###############################################################
#  Generated by:      Cadence Innovus 20.13-s083_1
#  OS:                Linux x86_64(Host ID rice-503-20-north)
#  Generated on:      Thu May  5 21:50:22 2022
#  Design:            ringosc
#  Command:           write_lef_abstract -5.8 -extractBlockObs /home/users/xingyuni/ee372/aloe-sky130/aloe/layout/output/lef/ro_top2_0.lef
###############################################################

VERSION 5.8 ;

BUSBITCHARS "[]" ;
DIVIDERCHAR "/" ;

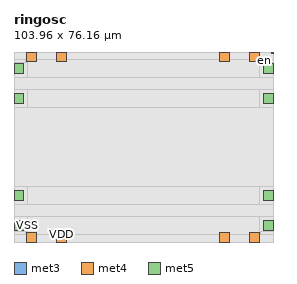
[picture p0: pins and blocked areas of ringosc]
MACRO ringosc
  CLASS BLOCK ;
  SIZE 103.960000 BY 76.160000 ;
  FOREIGN ringosc 0.000000 0.000000 ;
  ORIGIN 0 0 ;
  SYMMETRY X Y R90 ;
  PIN en
    DIRECTION INPUT ;
    USE SIGNAL ;
    PORT
      LAYER met3 ;
        RECT 103.160000 75.550000 103.960000 75.850000 ;
    END
  END en
  PIN clk
    DIRECTION INPUT ;
    USE SIGNAL ;
  END clk
  PIN VSS
    DIRECTION INOUT ;
    USE GROUND ;
    PORT
      LAYER met4 ;
        RECT 4.980000 0.000000 8.980000 4.000000 ;
    END
    PORT
      LAYER met4 ;
        RECT 4.980000 72.160000 8.980000 76.160000 ;
    END
    PORT
      LAYER met4 ;
        RECT 94.550000 0.000000 98.550000 4.000000 ;
    END
    PORT
      LAYER met4 ;
        RECT 94.550000 72.160000 98.550000 76.160000 ;
    END
    PORT
      LAYER met5 ;
        RECT 0.000000 4.560000 4.000000 8.560000 ;
    END
    PORT
      LAYER met5 ;
        RECT 99.960000 4.560000 103.960000 8.560000 ;
    END
    PORT
      LAYER met5 ;
        RECT 0.000000 67.360000 4.000000 71.360000 ;
    END
    PORT
      LAYER met5 ;
        RECT 99.960000 67.360000 103.960000 71.360000 ;
    END
  END VSS
  PIN VDD
    DIRECTION INOUT ;
    USE POWER ;
    PORT
      LAYER met4 ;
        RECT 16.980000 0.000000 20.980000 4.000000 ;
    END
    PORT
      LAYER met4 ;
        RECT 16.980000 72.160000 20.980000 76.160000 ;
    END
    PORT
      LAYER met4 ;
        RECT 82.550000 0.000000 86.550000 4.000000 ;
    END
    PORT
      LAYER met4 ;
        RECT 82.550000 72.160000 86.550000 76.160000 ;
    END
    PORT
      LAYER met5 ;
        RECT 0.000000 16.560000 4.000000 20.560000 ;
    END
    PORT
      LAYER met5 ;
        RECT 99.960000 16.560000 103.960000 20.560000 ;
    END
    PORT
      LAYER met5 ;
        RECT 0.000000 55.360000 4.000000 59.360000 ;
    END
    PORT
      LAYER met5 ;
        RECT 99.960000 55.360000 103.960000 59.360000 ;
    END
  END VDD
  OBS
    LAYER li1 ;
      RECT 0.000000 0.000000 103.960000 76.160000 ;
    LAYER met1 ;
      RECT 0.000000 0.000000 103.960000 76.160000 ;
    LAYER met2 ;
      RECT 0.000000 0.000000 103.960000 76.160000 ;
    LAYER met3 ;
      RECT 0.000000 75.150000 102.760000 76.160000 ;
      RECT 0.000000 0.000000 103.960000 75.150000 ;
    LAYER met4 ;
      RECT 98.950000 71.760000 103.960000 76.160000 ;
      RECT 86.950000 71.760000 94.150000 76.160000 ;
      RECT 21.380000 71.760000 82.150000 76.160000 ;
      RECT 9.380000 71.760000 16.580000 76.160000 ;
      RECT 0.000000 71.760000 4.580000 76.160000 ;
      RECT 0.000000 4.400000 103.960000 71.760000 ;
      RECT 98.950000 0.000000 103.960000 4.400000 ;
      RECT 86.950000 0.000000 94.150000 4.400000 ;
      RECT 21.380000 0.000000 82.150000 4.400000 ;
      RECT 9.380000 0.000000 16.580000 4.400000 ;
      RECT 0.000000 0.000000 4.580000 4.400000 ;
    LAYER met5 ;
      RECT 0.000000 72.960000 103.960000 76.160000 ;
      RECT 5.600000 65.760000 98.360000 72.960000 ;
      RECT 0.000000 60.960000 103.960000 65.760000 ;
      RECT 5.600000 53.760000 98.360000 60.960000 ;
      RECT 0.000000 22.160000 103.960000 53.760000 ;
      RECT 5.600000 14.960000 98.360000 22.160000 ;
      RECT 0.000000 10.160000 103.960000 14.960000 ;
      RECT 5.600000 2.960000 98.360000 10.160000 ;
      RECT 0.000000 0.000000 103.960000 2.960000 ;
  END
END ringosc

END LIBRARY
